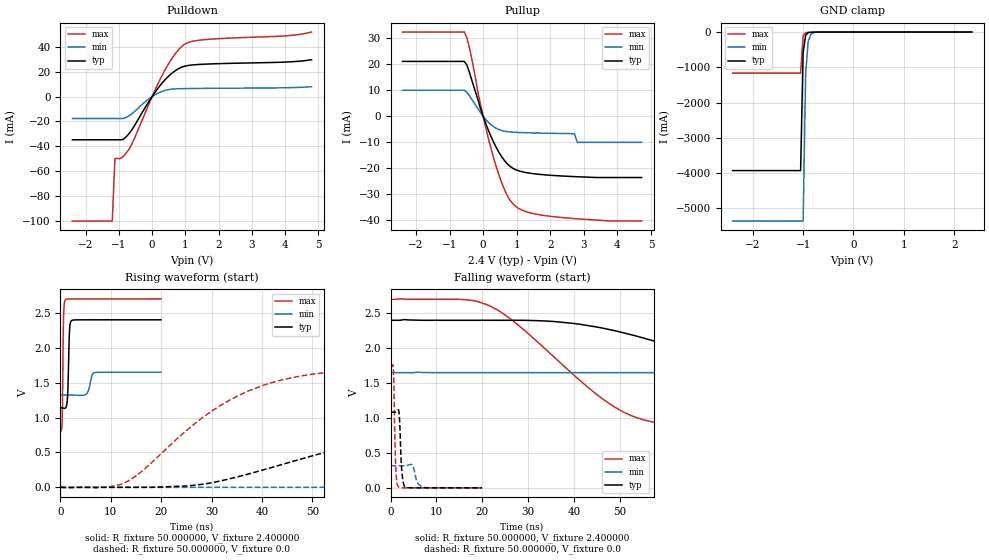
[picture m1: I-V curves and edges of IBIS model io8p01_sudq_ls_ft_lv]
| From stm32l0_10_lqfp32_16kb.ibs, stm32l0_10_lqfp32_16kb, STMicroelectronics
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|   Model io8p01_sudq_ls_ft_lv
[Model]  io8p01_sudq_ls_ft_lv
Model_type I/O
Polarity   Non-Inverting
Enable   Active-Low
Vinl =   0.720000V
Vinh =   1.680000V
Vmeas =  1.200000V
Cref =   50.000000pF
Rref =   100.000000M
Vref =   0.0V
C_comp   2.317700pF   2.286600pF   2.332700pF
[Temperature Range]   25.000000   0.105000k   -40.000000
[Pullup Reference]   2.400000V   1.650000V   2.700000V
[Pulldown Reference]   0.0V   0.0V   0.0V
[POWER Clamp Reference]   2.400000V   1.650000V   2.700000V
[GND Clamp Reference]   0.0V   0.0V   0.0V
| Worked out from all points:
|   slope of the pulldown table from 0 to 0.36 V, typ, clamps not added: 28.4 ohm
|   slope of the pullup table from 0 to 0.36 V, typ, clamps not added: 32.2 ohm
|   GND clamp passes 1 mA (typ) near -0.65 V on its own axis
|   rising waveform, R_fixture 50.000000, V_fixture 2.400000: 20-80 % time 276ps typ, 631ps min, 184ps max; typ from 1.14 V to 2.4 V
|   rising waveform, R_fixture 50.000000, V_fixture 0.0: 20-80 % time 39.8ns typ, 107ns min, 19.5ns max; typ from 0 V to 1.08 V
|   falling waveform, R_fixture 50.000000, V_fixture 2.400000: 20-80 % time 41.1ns typ, 106ns min, 20.3ns max; typ from 2.4 V to 1.14 V
|   falling waveform, R_fixture 50.000000, V_fixture 0.0: 20-80 % time 455ps typ, 831ps min, 354ps max; typ from 1.08 V to 0 V
[Pulldown]
|Voltage   I(typ)   I(min)   I(max)
-2.4V     -34.7mA    -17.61mA   -100mA
-1.2V     -34.7mA    -17.61mA   -100mA
-1.12V    -34.7mA    -17.61mA   -49.77mA
-960mV    -34.7mA    -17.61mA   -49.77mA
-720mV    -30.52mA   -15.81mA   -43.24mA
-560mV    -24.66mA   -12.69mA   -35.31mA
-80mV     -3.3mA     -1.497mA   -4.982mA
320mV     11.47mA    4.39mA     18.08mA
640mV     19.72mA    6.139mA    32.34mA
960mV     24.32mA    6.432mA    41.77mA
1.52V     26.01mA    6.613mA    45.64mA
4.8V      29.64mA    7.944mA    51.92mA
[Pullup]
|Voltage   I(typ)   I(min)   I(max)
-2.4V     21.07mA    9.995mA    32.35mA
-560mV    21.07mA    9.995mA    32.35mA
-480mV    19.56mA    9.178mA    30.06mA
-400mV    16.53mA    7.728mA    25.89mA
-80mV     3.011mA    1.496mA    4.671mA
320mV     -10.16mA   -4.078mA   -16.34mA
640mV     -17.08mA   -5.718mA   -28.28mA
960mV     -20.45mA   -6.129mA   -34.49mA
2V        -22.64mA   -6.529mA   -38.4mA
2.72V     -23.16mA   -6.7mA     -39.27mA
2.8V      -23.2mA    -10mA      -39.35mA
4.72V     -23.5mA    -10mA      -40.2mA
[GND_clamp]
|Voltage   I(typ)   I(min)   I(max)
-2.4V     -3.929A    -5.359A    -1.166A
-1.05V    -3.929A    -5.359A    -1.166A
-1V       -574.5mA   -5.359A    -109.1mA
-950mV    -90.02mA   -1.192A    -18.55mA
-900mV    -18.41mA   -269.7mA   -9.049mA
-850mV    -6.764mA   -63.59mA   -6.579mA
-800mV    -4.027mA   -16.66mA   -4.859mA
-650mV    -1.043mA   -1.218mA   -1.146mA
2.35V     0A         0A         0A
[POWER_clamp]
|Voltage   I(typ)   I(min)   I(max)
-2.4V     0A         0A         0A
0V        0A         0A         0A
[Ramp]
| variable   typ   min   max
dV/dt_r  0.65070/39.76689n   0.18979/0.10691u   1.03800/19.42647n
dV/dt_f  0.75696/41.02286n   0.19470/0.10638u   1.13786/20.23731n
R_load = 50.000000
[Rising Waveform]
R_fixture= 50.000000
V_fixture= 2.400000
V_fixture_min= 1.650000
V_fixture_max= 2.700000
|time   V(typ)   V(min)   V(max)
0s        1.139V     1.322V     801mV
320.3ps   1.138V     1.322V     921.7mV
600.6ps   1.134V     1.322V     2.385V
961ps     1.133V     1.322V     2.685V
1.401ns   1.289V     1.322V     2.697V
1.802ns   2.246V     1.322V     2.698V
2.162ns   2.385V     1.322V     2.699V
5.165ns   2.4V       1.339V     2.7V
6.807ns   2.4V       1.642V     2.7V
19.94ns   2.4V       1.65V      2.7V
[Rising Waveform]
R_fixture= 50.000000
V_fixture= 0.0
V_fixture_min= 0.0
V_fixture_max= 0.0
|time   V(typ)   V(min)   V(max)
0s        8.797uV    -3.707uV   -12.02uV
13.01ns   -221.4uV   -46.91uV   74.63mV
29.03ns   53.08mV    -46.29uV   1.041V
39.04ns   225.5mV    -45.98uV   1.428V
48.05ns   411.4mV    -38.15uV   1.599V
62.06ns   667.8mV    6.729uV    1.694V
89.09ns   948.9mV    1.519mV    1.727V
133.1ns   1.068V     59.51mV    1.73V
255.3ns   1.085V     267.4mV    1.73V
498.5ns   1.085V     316.6mV    1.73V
[Falling Waveform]
R_fixture= 50.000000
V_fixture= 2.400000
V_fixture_min= 1.650000
V_fixture_max= 2.700000
|time   V(typ)   V(min)   V(max)
0s        2.4V       1.65V      2.7V
21.02ns   2.4V       1.65V      2.624V
36.04ns   2.38V      1.65V      1.85V
50.05ns   2.232V     1.65V      1.112V
58.06ns   2.091V     1.65V      932.2mV
71.07ns   1.821V     1.65V      853.2mV
99.1ns    1.362V     1.65V      812.5mV
137.1ns   1.199V     1.635V     802.8mV
291.3ns   1.139V     1.379V     801mV
498.5ns   1.139V     1.322V     801mV
[Falling Waveform]
R_fixture= 50.000000
V_fixture= 0.0
V_fixture_min= 0.0
V_fixture_max= 0.0
|time   V(typ)   V(min)   V(max)
0s        1.085V     316.6mV    1.73V
600.6ps   1.085V     316.6mV    1.719V
1.121ns   1.084V     316.6mV    319.7mV
1.682ns   1.119V     316.6mV    16.18mV
1.922ns   1.016V     316.6mV    4.831mV
2.442ns   249.2mV    316.4mV    776.2uV
3.083ns   18.43mV    316.1mV    402.9uV
4.685ns   235.4uV    331.1mV    125.4uV
7.167ns   36.98uV    7.905mV    -9.358uV
19.94ns   8.797uV    -3.707uV   -12.02uV
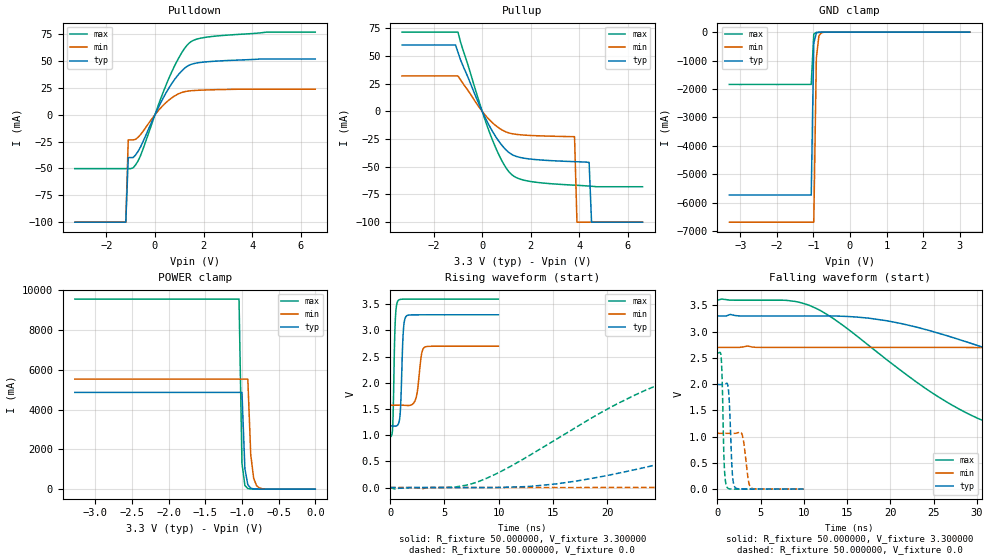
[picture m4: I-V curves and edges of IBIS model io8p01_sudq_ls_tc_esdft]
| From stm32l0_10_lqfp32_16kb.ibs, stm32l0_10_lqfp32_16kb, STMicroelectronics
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|   Model io8p01_sudq_ls_tc_esdft
[Model]  io8p01_sudq_ls_tc_esdft
Model_type I/O
Polarity   Non-Inverting
Enable   Active-Low
Vinl =   0.990000V
Vinh =   2.310000V
Vmeas =  1.650000V
Cref =   50.000000pF
Rref =   100.000000M
Vref =   0.0V
C_comp   2.248300pF   2.207300pF   2.311900pF
[Temperature Range]   25.000000   0.125000k   -40.000000
[Pullup Reference]   3.300000V   2.700000V   3.600000V
[Pulldown Reference]   0.0V   0.0V   0.0V
[POWER Clamp Reference]   3.300000V   2.700000V   3.600000V
[GND Clamp Reference]   0.0V   0.0V   0.0V
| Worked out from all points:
|   slope of the pulldown table from 0 to 0.495 V, typ, clamps not added: 22.6 ohm
|   slope of the pullup table from 0 to 0.495 V, typ, clamps not added: 23.9 ohm
|   GND clamp passes 1 mA (typ) near -0.64 V on its own axis
|   POWER clamp passes 1 mA (typ) near -0.63 V on its own axis
|   rising waveform, R_fixture 50.000000, V_fixture 3.300000: 20-80 % time 209ps typ, 365ps min, 164ps max; typ from 1.18 V to 3.3 V
|   rising waveform, R_fixture 50.000000, V_fixture 0.0: 20-80 % time 27.9ns typ, 60.6ns min, 14.1ns max; typ from 0 V to 1.99 V
|   falling waveform, R_fixture 50.000000, V_fixture 3.300000: 20-80 % time 24.4ns typ, 54ns min, 13.4ns max; typ from 3.3 V to 1.18 V
|   falling waveform, R_fixture 50.000000, V_fixture 0.0: 20-80 % time 290ps typ, 460ps min, 228ps max; typ from 1.99 V to 0 V
[Pulldown]
|Voltage   I(typ)   I(min)   I(max)
-3.3V     -100mA     -100mA     -50.11mA
-1.2V     -100mA     -100mA     -50.11mA
-1.1V     -39.8mA    -23.38mA   -50.11mA
-900mV    -39.8mA    -23.38mA   -49.43mA
-600mV    -30.26mA   -18.59mA   -38.38mA
500mV     22.11mA    12.28mA    30.06mA
900mV     35.58mA    18.71mA    49.62mA
1.3V      44.73mA    21.88mA    64.23mA
1.7V      48.13mA    22.72mA    70.3mA
2.4V      49.79mA    23.3mA     73.03mA
4.6V      51.9mA     23.82mA    77mA
6.6V      51.9mA     23.82mA    77mA
[Pullup]
|Voltage   I(typ)   I(min)   I(max)
-3.3V     60mA       32mA       71.6mA
-1.1V     60mA       32mA       71.6mA
-1V       53.5mA     32mA       71.6mA
-100mV    4.893mA    2.926mA    6.861mA
400mV     -17.21mA   -9.813mA   -24.69mA
900mV     -32.92mA   -17.72mA   -48.15mA
1.3V      -39.75mA   -20.41mA   -58.47mA
3.8V      -45.36mA   -22.8mA    -66.6mA
3.9V      -45.44mA   -100mA     -66.72mA
4.4V      -46mA      -100mA     -67.4mA
4.5V      -100mA     -100mA     -67.56mA
6.6V      -100mA     -100mA     -68mA
[GND_clamp]
|Voltage   I(typ)   I(min)   I(max)
-3.3V     -5.732A    -6.688A    -1.842A
-1.06V    -5.732A    -6.688A    -1.842A
-990mV    -389.4mA   -6.688A    -68.34mA
-920mV    -32.57mA   -918.2mA   -10.72mA
-850mV    -6.763mA   -131mA     -6.509mA
-780mV    -3.471mA   -21mA      -4.208mA
3.28V     0A         0A         0A
[POWER_clamp]
|Voltage   I(typ)   I(min)   I(max)
-3.28V    4.87A      5.538A     9.569A
-1.04V    4.87A      5.538A     9.569A
-1V       4.87A      5.538A     1.315A
-960mV    1.032A     5.538A     186.5mA
-920mV    222.2mA    5.538A     31.64mA
-880mV    50.73mA    1.734A     9.582mA
-840mV    13.93mA    544.8mA    5.668mA
-800mV    5.556mA    172.7mA    4.276mA
-760mV    3.231mA    55.84mA    3.297mA
-680mV    1.597mA    6.983mA    1.741mA
0V        0A         0A         0A
[Ramp]
| variable   typ   min   max
dV/dt_r  1.19496/27.86187n   0.63516/60.61922n   1.55568/14.11258n
dV/dt_f  1.27398/24.41783n   0.67074/53.95781n   1.57787/13.38589n
R_load = 50.000000
[Rising Waveform]
R_fixture= 50.000000
V_fixture= 3.300000
V_fixture_min= 2.700000
V_fixture_max= 3.600000
|time   V(typ)   V(min)   V(max)
0s        1.177V     1.573V     968.3mV
240.2ps   1.176V     1.573V     1.15V
460.5ps   1.173V     1.573V     3.095V
740.7ps   1.207V     1.573V     3.571V
961ps     1.515V     1.573V     3.595V
1.241ns   3.041V     1.572V     3.598V
1.502ns   3.276V     1.569V     3.598V
2.382ns   3.299V     1.706V     3.599V
3.163ns   3.3V       2.678V     3.6V
9.97ns    3.3V       2.7V       3.6V
[Rising Waveform]
R_fixture= 50.000000
V_fixture= 0.0
V_fixture_min= 0.0
V_fixture_max= 0.0
|time   V(typ)   V(min)   V(max)
0s        59.16uV    15.63uV    -3.026mV
8.008ns   -271.4uV   -125.8uV   103.6mV
15.52ns   75.18mV    -117.6uV   948.6mV
22.52ns   340.5mV    531.6uV    1.765V
27.53ns   585.7mV    7.873mV    2.162V
40.04ns   1.208V     60.22mV    2.522V
56.56ns   1.702V     219.9mV    2.582V
78.08ns   1.923V     496.9mV    2.591V
142.1ns   1.991V     963.8mV    2.592V
249.2ns   1.992V     1.062V     2.592V
[Falling Waveform]
R_fixture= 50.000000
V_fixture= 3.300000
V_fixture_min= 2.700000
V_fixture_max= 3.600000
|time   V(typ)   V(min)   V(max)
0s        3.3V       2.7V       3.6V
10.51ns   3.3V       2.7V       3.51V
19.52ns   3.21V      2.7V       2.474V
28.53ns   2.82V      2.699V     1.475V
33.03ns   2.575V     2.692V     1.177V
39.04ns   2.237V     2.667V     1.052V
56.56ns   1.457V     2.512V     985.4mV
77.08ns   1.257V     2.23V      972.2mV
130.6ns   1.185V     1.71V      968.4mV
249.2ns   1.177V     1.573V     968.3mV
[Falling Waveform]
R_fixture= 50.000000
V_fixture= 0.0
V_fixture_min= 0.0
V_fixture_max= 0.0
|time   V(typ)   V(min)   V(max)
0s        1.992V     1.062V     2.592V
460.5ps   1.992V     1.062V     2.472V
800.8ps   1.993V     1.062V     446.4mV
1.121ns   2.016V     1.062V     34.65mV
1.361ns   1.723V     1.062V     4.067mV
1.742ns   278.4mV    1.061V     -1.698mV
2.042ns   31.8mV     1.061V     -2.113mV
2.883ns   1.002mV    1.027V     -2.487mV
3.904ns   425uV      23.05mV    -2.751mV
9.97ns    59.16uV    15.63uV    -3.026mV
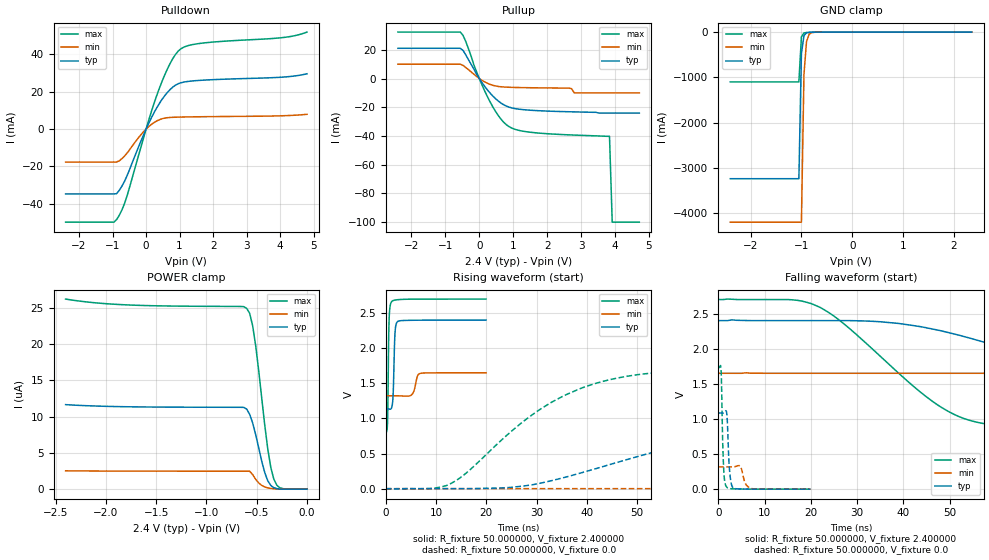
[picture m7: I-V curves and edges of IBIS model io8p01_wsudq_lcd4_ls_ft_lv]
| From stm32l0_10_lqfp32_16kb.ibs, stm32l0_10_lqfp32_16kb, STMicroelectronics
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|   Model io8p01_wsudq_lcd4_ls_ft_lv
[Model]  io8p01_wsudq_lcd4_ls_ft_lv
Model_type I/O
Polarity   Non-Inverting
Enable   Active-Low
Vinl =   0.720000V
Vinh =   1.680000V
Vmeas =  1.200000V
Cref =   50.000000pF
Rref =   100.000000M
Vref =   0.0V
C_comp   3.178800pF   3.170000pF   3.206700pF
[Temperature Range]   25.000000   0.105000k   -40.000000
[Pullup Reference]   2.400000V   1.650000V   2.700000V
[Pulldown Reference]   0.0V   0.0V   0.0V
[POWER Clamp Reference]   2.400000V   1.650000V   2.700000V
[GND Clamp Reference]   0.0V   0.0V   0.0V
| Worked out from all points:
|   slope of the pulldown table from 0 to 0.36 V, typ, clamps not added: 28.5 ohm
|   slope of the pullup table from 0 to 0.36 V, typ, clamps not added: 32.2 ohm
|   GND clamp passes 1 mA (typ) near -0.64 V on its own axis
|   rising waveform, R_fixture 50.000000, V_fixture 2.400000: 20-80 % time 297ps typ, 645ps min, 211ps max; typ from 1.14 V to 2.4 V
|   rising waveform, R_fixture 50.000000, V_fixture 0.0: 20-80 % time 39.6ns typ, 107ns min, 19.4ns max; typ from 0 V to 1.08 V
|   falling waveform, R_fixture 50.000000, V_fixture 2.400000: 20-80 % time 40.7ns typ, 106ns min, 20.1ns max; typ from 2.4 V to 1.14 V
|   falling waveform, R_fixture 50.000000, V_fixture 0.0: 20-80 % time 491ps typ, 857ps min, 390ps max; typ from 1.08 V to 0 V
[Pulldown]
|Voltage   I(typ)   I(min)   I(max)
-2.4V     -34.7mA    -17.61mA   -49.82mA
-960mV    -34.7mA    -17.61mA   -49.82mA
-880mV    -34.55mA   -17.61mA   -48.46mA
-720mV    -30.52mA   -15.79mA   -43.28mA
-560mV    -24.65mA   -12.68mA   -35.33mA
0V        326fA      0A         20fA
400mV     13.84mA    5.066mA    22.03mA
720mV     21.25mA    6.254mA    35.26mA
1.04V     24.82mA    6.464mA    43.03mA
1.6V      26.11mA    6.627mA    45.88mA
4V        27.76mA    7.125mA    48.87mA
4.8V      29.64mA    7.94mA     51.96mA
[Pullup]
|Voltage   I(typ)   I(min)   I(max)
-2.4V     21.07mA    9.995mA    32.35mA
-560mV    21.07mA    9.995mA    32.35mA
-400mV    16.53mA    7.728mA    25.89mA
-80mV     3.011mA    1.496mA    4.671mA
320mV     -10.16mA   -4.078mA   -16.34mA
640mV     -17.08mA   -5.718mA   -28.28mA
960mV     -20.45mA   -6.129mA   -34.49mA
1.76V     -22.39mA   -6.471mA   -37.97mA
2.8V      -23.2mA    -10mA      -39.35mA
3.84V     -24mA      -10mA      -40.2mA
3.92V     -24mA      -10mA      -100mA
4.72V     -24mA      -10mA      -100mA
[GND_clamp]
|Voltage   I(typ)   I(min)   I(max)
-2.4V     -3.238A    -4.199A    -1.101A
-1.05V    -3.238A    -4.199A    -1.101A
-1V       -476.5mA   -4.199A    -104.7mA
-950mV    -76.68mA   -936.1mA   -18.74mA
-900mV    -16.85mA   -213.2mA   -9.358mA
-850mV    -6.706mA   -51.12mA   -6.778mA
-800mV    -4.108mA   -13.92mA   -4.995mA
-650mV    -1.07mA    -1.211mA   -1.175mA
2.35V     0A         0A         0A
[POWER_clamp]
|Voltage   I(typ)   I(min)   I(max)
-2.4V     11.64uA    2.527uA    26.18uA
-1.86V    11.37uA    2.49uA     25.43uA
-600mV    11.04uA    2.475uA    24.9uA
-570mV    10.3uA     2.473uA    24.21uA
-540mV    9.097uA    2.001uA    22.48uA
-510mV    7.497uA    1.351uA    19.73uA
-450mV    3.846uA    513.2nA    12.52uA
-390mV    1.155uA    176.1nA    5.528uA
-360mV    508.6nA    103.4nA    2.997uA
-330mV    204.7nA    61.05nA    1.375uA
-270mV    0A         0A         195.3nA
0V        0A         0A         0A
[Ramp]
| variable   typ   min   max
dV/dt_r  0.65070/39.56713n   0.18972/0.10637u   1.03800/19.39800n
dV/dt_f  0.75690/40.65908n   0.19476/0.10552u   1.13815/20.03188n
R_load = 50.000000
[Rising Waveform]
R_fixture= 50.000000
V_fixture= 2.400000
V_fixture_min= 1.650000
V_fixture_max= 2.700000
|time   V(typ)   V(min)   V(max)
0s        1.139V     1.322V     800.6mV
360.4ps   1.137V     1.322V     1.014V
560.6ps   1.135V     1.322V     2.147V
680.7ps   1.133V     1.322V     2.462V
1.121ns   1.148V     1.322V     2.66V
1.441ns   1.334V     1.322V     2.678V
1.842ns   2.24V      1.322V     2.686V
2.282ns   2.376V     1.322V     2.69V
6.887ns   2.399V     1.642V     2.699V
19.94ns   2.4V       1.65V      2.7V
[Rising Waveform]
R_fixture= 50.000000
V_fixture= 0.0
V_fixture_min= 0.0
V_fixture_max= 0.0
|time   V(typ)   V(min)   V(max)
0s        9.024uV    -4.384uV   -11.23uV
13.01ns   -211.1uV   -47.47uV   75.74mV
29.03ns   54.19mV    -46uV      1.047V
39.04ns   228.7mV    -45.93uV   1.435V
48.05ns   415.3mV    -40.69uV   1.601V
62.06ns   671.5mV    30.17uV    1.695V
86.09ns   931.3mV    1.181mV    1.726V
121.1ns   1.054V     38.12mV    1.73V
254.3ns   1.085V     267.4mV    1.73V
498.5ns   1.085V     316.6mV    1.73V
[Falling Waveform]
R_fixture= 50.000000
V_fixture= 2.400000
V_fixture_min= 1.650000
V_fixture_max= 2.700000
|time   V(typ)   V(min)   V(max)
0s        2.4V       1.65V      2.7V
20.02ns   2.4V       1.65V      2.644V
26.03ns   2.4V       1.65V      2.413V
50.05ns   2.224V     1.65V      1.094V
57.06ns   2.099V     1.65V      937mV
70.07ns   1.828V     1.65V      854.3mV
98.1ns    1.362V     1.65V      812.1mV
140.1ns   1.192V     1.631V     802.1mV
287.3ns   1.139V     1.38V      800.5mV
498.5ns   1.139V     1.322V     800.6mV
[Falling Waveform]
R_fixture= 50.000000
V_fixture= 0.0
V_fixture_min= 0.0
V_fixture_max= 0.0
|time   V(typ)   V(min)   V(max)
0s        1.085V     316.6mV    1.73V
600.6ps   1.085V     316.6mV    1.719V
961ps     1.084V     316.6mV    697.4mV
1.161ns   1.084V     316.6mV    322.3mV
1.802ns   1.099V     316.6mV    32.36mV
2.482ns   246.9mV    316.4mV    8.749mV
3.203ns   20.78mV    316.5mV    4.644mV
4.805ns   2.475mV    322.1mV    2.159mV
7.167ns   1.012mV    9.001mV    808.9uV
19.94ns   9.024uV    -4.384uV   -11.23uV
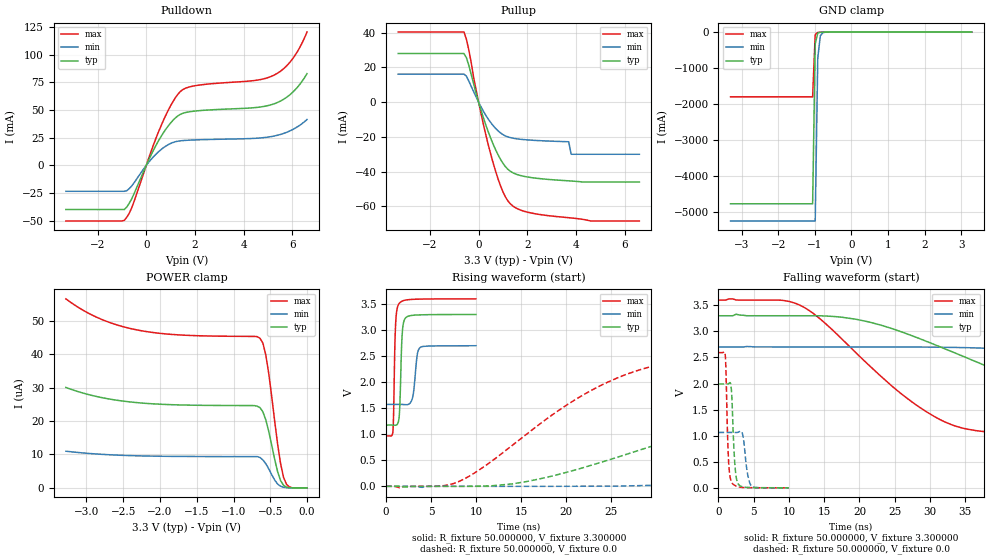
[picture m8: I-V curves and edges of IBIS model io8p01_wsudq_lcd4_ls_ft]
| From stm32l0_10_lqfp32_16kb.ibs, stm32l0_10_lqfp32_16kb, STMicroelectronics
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|   Model io8p01_wsudq_lcd4_ls_ft
[Model]  io8p01_wsudq_lcd4_ls_ft
Model_type I/O
Polarity   Non-Inverting
Enable   Active-Low
Vinl =   0.990000V
Vinh =   2.310000V
Vmeas =  1.650000V
Cref =   50.000000pF
Rref =   100.000000M
Vref =   0.0V
C_comp   3.263700pF   3.224700pF   3.309000pF
[Temperature Range]   25.000000   0.125000k   -40.000000
[Pullup Reference]   3.300000V   2.700000V   3.600000V
[Pulldown Reference]   0.0V   0.0V   0.0V
[POWER Clamp Reference]   3.300000V   2.700000V   3.600000V
[GND Clamp Reference]   0.0V   0.0V   0.0V
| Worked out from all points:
|   slope of the pulldown table from 0 to 0.495 V, typ, clamps not added: 22.6 ohm
|   slope of the pullup table from 0 to 0.495 V, typ, clamps not added: 23.9 ohm
|   GND clamp passes 1 mA (typ) near -0.64 V on its own axis
|   rising waveform, R_fixture 50.000000, V_fixture 3.300000: 20-80 % time 237ps typ, 377ps min, 200ps max; typ from 1.18 V to 3.3 V
|   rising waveform, R_fixture 50.000000, V_fixture 0.0: 20-80 % time 27.1ns typ, 59.6ns min, 13.6ns max; typ from 0 V to 1.99 V
|   falling waveform, R_fixture 50.000000, V_fixture 3.300000: 20-80 % time 24.2ns typ, 53.2ns min, 13.3ns max; typ from 3.3 V to 1.18 V
|   falling waveform, R_fixture 50.000000, V_fixture 0.0: 20-80 % time 414ps typ, 578ps min, 337ps max; typ from 1.99 V to 0 V
[Pulldown]
|Voltage   I(typ)   I(min)   I(max)
-3.3V     -39.83mA   -23.37mA   -50.2mA
-900mV    -39.83mA   -23.37mA   -49.52mA
-600mV    -30.28mA   -18.59mA   -38.45mA
500mV     22.11mA    12.28mA    30.1mA
1V        38.33mA    19.81mA    53.88mA
1.4V      46.1mA     22.18mA    66.72mA
2V        49.07mA    23.01mA    71.93mA
4.4V      52.05mA    24.38mA    76.53mA
5.2V      55.25mA    26.31mA    81.02mA
5.6V      59.18mA    28.57mA    86.57mA
6V        65.79mA    32.24mA    95.97mA
6.6V      82.83mA    41.41mA    120.4mA
[Pullup]
|Voltage   I(typ)   I(min)   I(max)
-3.3V     27.97mA    16.08mA    40.34mA
-600mV    27.97mA    16.08mA    40.34mA
-400mV    21.07mA    12.09mA    29.9mA
-200mV    10.4mA     5.946mA    13.84mA
200mV     -9.115mA   -5.294mA   -12.98mA
600mV     -24.29mA   -13.56mA   -35.12mA
1V        -35.2mA    -18.69mA   -51.63mA
1.4V      -40.6mA    -20.72mA   -59.71mA
2.1V      -43.28mA   -21.83mA   -63.62mA
3.7V      -45.29mA   -22.8mA    -66.5mA
3.8V      -45.39mA   -30mA      -66.64mA
6.6V      -46mA      -30mA      -68.41mA
[GND_clamp]
|Voltage   I(typ)   I(min)   I(max)
-3.3V     -4.767A    -5.245A    -1.798A
-1.06V    -4.767A    -5.245A    -1.798A
-990mV    -327.3mA   -5.245A    -68.38mA
-920mV    -29.22mA   -722.7mA   -11.24mA
-850mV    -6.771mA   -104.4mA   -6.721mA
-780mV    -3.56mA    -17.38mA   -4.326mA
-500mV    -59.41uA   -172uA     -34.91uA
3.28V     0A         0A         0A
[POWER_clamp]
|Voltage   I(typ)   I(min)   I(max)
-3.28V    30.09uA    10.99uA    56.63uA
-2.84V    27.27uA    10.11uA    50.92uA
-2.32V    25.55uA    9.609uA    47.36uA
-640mV    24.06uA    9.1uA      44.84uA
-600mV    22.76uA    8.366uA    43.37uA
-560mV    20.32uA    7.212uA    39.74uA
-520mV    16.86uA    5.676uA    34.15uA
-400mV    4.842uA    1.146uA    13.11uA
-360mV    2.185uA    478.4nA    7.29uA
-320mV    773nA      181.6nA    3.214uA
-240mV    60.58nA    0A         296.5nA
0V        0A         0A         0A
[Ramp]
| variable   typ   min   max
dV/dt_r  1.19496/27.05195n   0.63564/59.62315n   1.55568/13.56149n
dV/dt_f  1.27416/24.16242n   0.67062/53.19542n   1.57856/13.27114n
R_load = 50.000000
[Rising Waveform]
R_fixture= 50.000000
V_fixture= 3.300000
V_fixture_min= 2.700000
V_fixture_max= 3.600000
|time   V(typ)   V(min)   V(max)
0s        1.176V     1.573V     969.1mV
740.7ps   1.176V     1.573V     1.038V
1.041ns   1.173V     1.573V     3.082V
1.401ns   1.276V     1.574V     3.502V
1.522ns   1.565V     1.574V     3.527V
1.782ns   2.92V      1.572V     3.556V
2.142ns   3.232V     1.568V     3.576V
2.903ns   3.283V     1.684V     3.59V
3.744ns   3.293V     2.661V     3.595V
9.97ns    3.3V       2.7V       3.6V
[Rising Waveform]
R_fixture= 50.000000
V_fixture= 0.0
V_fixture_min= 0.0
V_fixture_max= 0.0
|time   V(typ)   V(min)   V(max)
0s        -501.9nV   -2.275uV   -340.5nV
8.008ns   -465.1uV   -172.1uV   86.73mV
15.52ns   88.98mV    -152.9uV   989.4mV
24.52ns   495.6mV    2.792mV    1.993V
30.03ns   798.9mV    20.49mV    2.326V
37.54ns   1.172V     61.78mV    2.506V
54.55ns   1.702V     241.2mV    2.582V
75.08ns   1.92V      508.4mV    2.592V
138.1ns   1.991V     964.7mV    2.593V
249.2ns   1.992V     1.062V     2.593V
[Falling Waveform]
R_fixture= 50.000000
V_fixture= 3.300000
V_fixture_min= 2.700000
V_fixture_max= 3.600000
|time   V(typ)   V(min)   V(max)
0s        3.3V       2.7V       3.6V
12.01ns   3.3V       2.7V       3.472V
19.52ns   3.233V     2.7V       2.588V
28.53ns   2.862V     2.7V       1.545V
33.53ns   2.588V     2.692V     1.189V
39.04ns   2.275V     2.671V     1.06V
56.06ns   1.483V     2.524V     987.9mV
72.07ns   1.282V     2.309V     974.9mV
122.1ns   1.188V     1.747V     969.3mV
249.2ns   1.176V     1.573V     969.1mV
[Falling Waveform]
R_fixture= 50.000000
V_fixture= 0.0
V_fixture_min= 0.0
V_fixture_max= 0.0
|time   V(typ)   V(min)   V(max)
0s        1.992V     1.062V     2.593V
961ps     1.992V     1.062V     2.54V
1.421ns   1.997V     1.062V     539.8mV
1.862ns   1.815V     1.062V     107.6mV
2.322ns   454.6mV    1.061V     47.08mV
2.803ns   73.5mV     1.067V     21.53mV
3.423ns   20.01mV    1.026V     8.271mV
4.164ns   7.15mV     238mV      4.336mV
4.705ns   4.101mV    34.31mV    3.131mV
9.97ns    -501.9nV   -2.275uV   -340.5nV
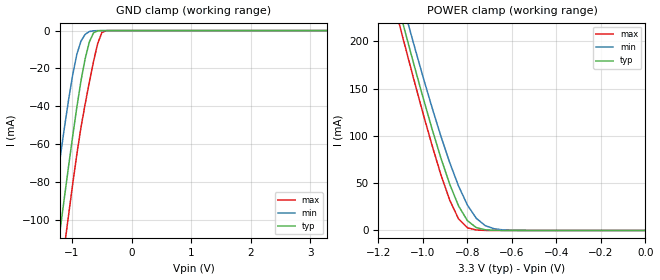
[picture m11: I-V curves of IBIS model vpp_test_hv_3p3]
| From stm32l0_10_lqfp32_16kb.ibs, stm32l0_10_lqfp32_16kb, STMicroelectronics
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|   Model vpp_test_hv_3p3
[Model]  vpp_test_hv_3p3
Model_type Input
Polarity   Non-Inverting
Vinl =   0.990000V
Vinh =   2.310000V
C_comp   1.864200pF   1.853400pF   1.871500pF
[Temperature Range]   25.000000   0.125000k   -40.000000
[Pullup Reference]   3.300000V   2.700000V   3.600000V
[Pulldown Reference]   0.0V   0.0V   0.0V
[POWER Clamp Reference]   3.300000V   2.700000V   3.600000V
[GND Clamp Reference]   0.0V   0.0V   0.0V
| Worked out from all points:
|   GND clamp passes 1 mA (typ) near -0.63 V on its own axis
|   POWER clamp passes 1 mA (typ) near -0.72 V on its own axis
[GND_clamp]
|Voltage   I(typ)   I(min)   I(max)
-3.3V     -632mA     -587.5mA   -660.8mA
-1.41V    -156.3mA   -116.1mA   -183.5mA
-1.34V    -139.1mA   -99.48mA   -166.1mA
-1.2V     -105.1mA   -67.11mA   -131.6mA
-1.13V    -88.39mA   -51.59mA   -114.5mA
-1.06V    -71.92mA   -36.83mA   -97.66mA
-920mV    -40.46mA   -12.51mA   -65.25mA
-850mV    -26.41mA   -5.525mA   -50.95mA
-710mV    -6.01mA    -517.3uA   -27.22mA
-570mV    -124.2uA   -22.37uA   -6.825mA
-430mV    -824.9nA   -767.9nA   -51.78uA
3.28V     0A         0A         165.9nA
[POWER_clamp]
|Voltage   I(typ)   I(min)   I(max)
-3.28V    2.336A     2.336A     2.337A
-1.12V    245.5mA    264.7mA    230.6mA
-1.08V    209.8mA    229.9mA    194.3mA
-1.04V    174.8mA    195.8mA    158.7mA
-920mV    76.99mA    100mA      59.38mA
-880mV    49.02mA    71.82mA    32.14mA
-840mV    25.91mA    46.92mA    12.2mA
-800mV    10.29mA    26.75mA    2.802mA
-760mV    2.993mA    12.77mA    482uA
-720mV    735.9uA    5.105mA    82.5uA
-680mV    178.1uA    1.815mA    13.9uA
0V        0A         0A         174.9nA
